VERSION 5.7 ;
  NOWIREEXTENSIONATPIN ON ;
  DIVIDERCHAR "/" ;
  BUSBITCHARS "[]" ;
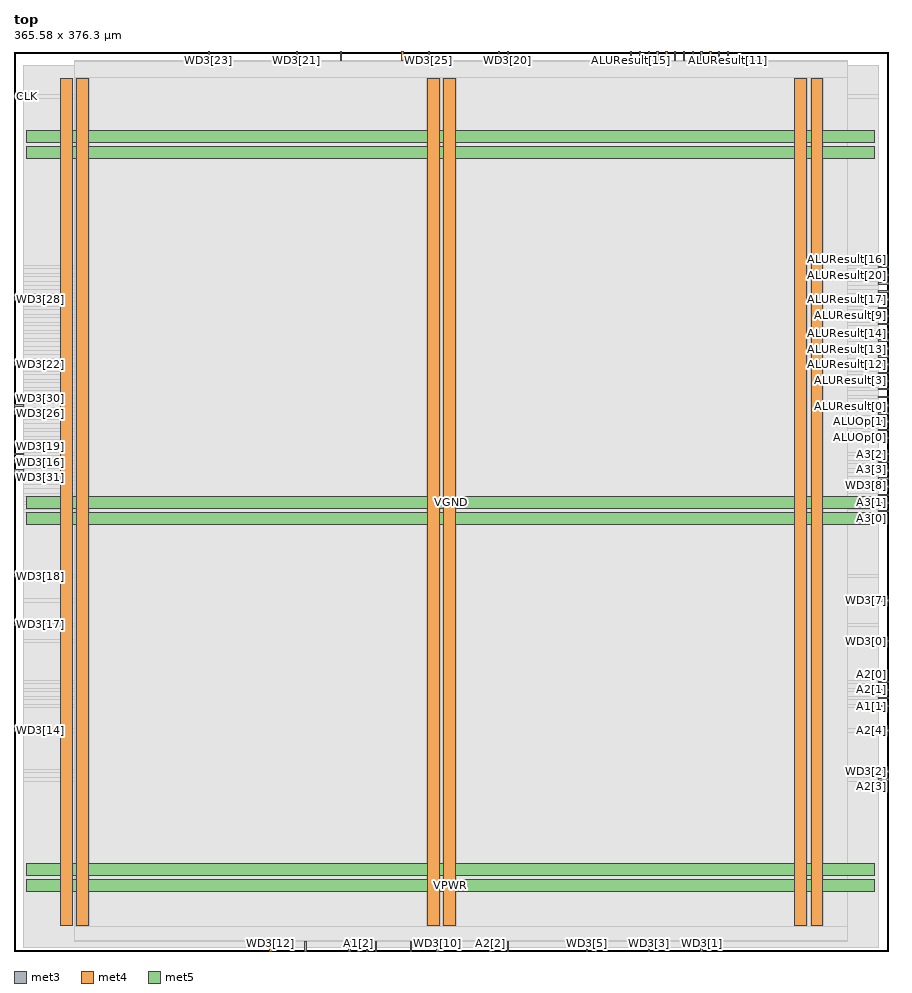
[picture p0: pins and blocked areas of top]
MACRO top
  CLASS BLOCK ;
  FOREIGN top ;
  ORIGIN 0.000 0.000 ;
  SIZE 365.580 BY 376.300 ;
  PIN A1[0]
    DIRECTION INPUT ;
    USE SIGNAL ;
    ANTENNAGATEAREA 0.126000 ;
    PORT
      LAYER met3 ;
        RECT 361.580 105.440 365.580 106.040 ;
    END
  END A1[0]
  PIN A1[1]
    DIRECTION INPUT ;
    USE SIGNAL ;
    ANTENNAGATEAREA 0.196500 ;
    PORT
      LAYER met3 ;
        RECT 361.580 102.040 365.580 102.640 ;
    END
  END A1[1]
  PIN A1[2]
    DIRECTION INPUT ;
    USE SIGNAL ;
    ANTENNAGATEAREA 0.247500 ;
    PORT
      LAYER met4 ;
        RECT 143.680 0.000 144.280 4.000 ;
    END
  END A1[2]
  PIN A1[3]
    DIRECTION INPUT ;
    USE SIGNAL ;
    ANTENNAGATEAREA 0.247500 ;
    PORT
      LAYER met4 ;
        RECT 140.000 0.000 140.600 4.000 ;
    END
  END A1[3]
  PIN A1[4]
    DIRECTION INPUT ;
    USE SIGNAL ;
    ANTENNAGATEAREA 0.213000 ;
    PORT
      LAYER met4 ;
        RECT 147.360 0.000 147.960 4.000 ;
    END
  END A1[4]
  PIN A2[0]
    DIRECTION INPUT ;
    USE SIGNAL ;
    ANTENNAGATEAREA 6.873000 ;
    PORT
      LAYER met3 ;
        RECT 361.580 112.240 365.580 112.840 ;
    END
  END A2[0]
  PIN A2[1]
    DIRECTION INPUT ;
    USE SIGNAL ;
    ANTENNAGATEAREA 0.921000 ;
    PORT
      LAYER met3 ;
        RECT 361.580 108.840 365.580 109.440 ;
    END
  END A2[1]
  PIN A2[2]
    DIRECTION INPUT ;
    USE SIGNAL ;
    ANTENNAGATEAREA 0.196500 ;
    PORT
      LAYER met4 ;
        RECT 198.880 0.000 199.480 4.000 ;
    END
  END A2[2]
  PIN A2[3]
    DIRECTION INPUT ;
    USE SIGNAL ;
    ANTENNAGATEAREA 0.126000 ;
    PORT
      LAYER met3 ;
        RECT 361.580 71.440 365.580 72.040 ;
    END
  END A2[3]
  PIN A2[4]
    DIRECTION INPUT ;
    USE SIGNAL ;
    ANTENNAGATEAREA 0.247500 ;
    PORT
      LAYER met3 ;
        RECT 361.580 91.840 365.580 92.440 ;
    END
  END A2[4]
  PIN A3[0]
    DIRECTION INPUT ;
    USE SIGNAL ;
    ANTENNAGATEAREA 0.213000 ;
    PORT
      LAYER met3 ;
        RECT 361.580 183.640 365.580 184.240 ;
    END
  END A3[0]
  PIN A3[1]
    DIRECTION INPUT ;
    USE SIGNAL ;
    ANTENNAGATEAREA 0.159000 ;
    PORT
      LAYER met3 ;
        RECT 361.580 187.040 365.580 187.640 ;
    END
  END A3[1]
  PIN A3[2]
    DIRECTION INPUT ;
    USE SIGNAL ;
    ANTENNAGATEAREA 0.159000 ;
    PORT
      LAYER met3 ;
        RECT 361.580 207.440 365.580 208.040 ;
    END
  END A3[2]
  PIN A3[3]
    DIRECTION INPUT ;
    USE SIGNAL ;
    ANTENNAGATEAREA 0.159000 ;
    PORT
      LAYER met3 ;
        RECT 361.580 204.040 365.580 204.640 ;
    END
  END A3[3]
  PIN A3[4]
    DIRECTION INPUT ;
    USE SIGNAL ;
    ANTENNAGATEAREA 0.159000 ;
    PORT
      LAYER met3 ;
        RECT 361.580 200.640 365.580 201.240 ;
    END
  END A3[4]
  PIN ALUOp[0]
    DIRECTION INPUT ;
    USE SIGNAL ;
    ANTENNAGATEAREA 0.213000 ;
    PORT
      LAYER met3 ;
        RECT 361.580 214.240 365.580 214.840 ;
    END
  END ALUOp[0]
  PIN ALUOp[1]
    DIRECTION INPUT ;
    USE SIGNAL ;
    ANTENNAGATEAREA 0.213000 ;
    PORT
      LAYER met3 ;
        RECT 361.580 221.040 365.580 221.640 ;
    END
  END ALUOp[1]
  PIN ALUResult[0]
    DIRECTION OUTPUT ;
    USE SIGNAL ;
    ANTENNADIFFAREA 1.336500 ;
    PORT
      LAYER met3 ;
        RECT 361.580 224.440 365.580 225.040 ;
    END
  END ALUResult[0]
  PIN ALUResult[10]
    DIRECTION OUTPUT ;
    USE SIGNAL ;
    ANTENNADIFFAREA 0.445500 ;
    PORT
      LAYER met3 ;
        RECT 361.580 258.440 365.580 259.040 ;
    END
  END ALUResult[10]
  PIN ALUResult[11]
    DIRECTION OUTPUT ;
    USE SIGNAL ;
    ANTENNADIFFAREA 0.795200 ;
    PORT
      LAYER met4 ;
        RECT 298.240 372.300 298.840 376.300 ;
    END
  END ALUResult[11]
  PIN ALUResult[12]
    DIRECTION OUTPUT ;
    USE SIGNAL ;
    ANTENNADIFFAREA 1.336500 ;
    PORT
      LAYER met3 ;
        RECT 361.580 244.840 365.580 245.440 ;
    END
  END ALUResult[12]
  PIN ALUResult[13]
    DIRECTION OUTPUT ;
    USE SIGNAL ;
    ANTENNADIFFAREA 0.445500 ;
    PORT
      LAYER met3 ;
        RECT 361.580 248.240 365.580 248.840 ;
    END
  END ALUResult[13]
  PIN ALUResult[14]
    DIRECTION OUTPUT ;
    USE SIGNAL ;
    ANTENNADIFFAREA 1.336500 ;
    PORT
      LAYER met3 ;
        RECT 361.580 255.040 365.580 255.640 ;
    END
  END ALUResult[14]
  PIN ALUResult[15]
    DIRECTION OUTPUT ;
    USE SIGNAL ;
    ANTENNADIFFAREA 0.795200 ;
    PORT
      LAYER met4 ;
        RECT 257.760 372.300 258.360 376.300 ;
    END
  END ALUResult[15]
  PIN ALUResult[16]
    DIRECTION OUTPUT ;
    USE SIGNAL ;
    ANTENNADIFFAREA 1.336500 ;
    PORT
      LAYER met3 ;
        RECT 361.580 285.640 365.580 286.240 ;
    END
  END ALUResult[16]
  PIN ALUResult[17]
    DIRECTION OUTPUT ;
    USE SIGNAL ;
    ANTENNADIFFAREA 0.445500 ;
    PORT
      LAYER met3 ;
        RECT 361.580 272.040 365.580 272.640 ;
    END
  END ALUResult[17]
  PIN ALUResult[18]
    DIRECTION OUTPUT ;
    USE SIGNAL ;
    ANTENNADIFFAREA 0.795200 ;
    PORT
      LAYER met3 ;
        RECT 361.580 261.840 365.580 262.440 ;
    END
  END ALUResult[18]
  PIN ALUResult[19]
    DIRECTION OUTPUT ;
    USE SIGNAL ;
    ANTENNADIFFAREA 0.445500 ;
    PORT
      LAYER met3 ;
        RECT 361.580 275.440 365.580 276.040 ;
    END
  END ALUResult[19]
  PIN ALUResult[1]
    DIRECTION OUTPUT ;
    USE SIGNAL ;
    ANTENNADIFFAREA 1.336500 ;
    PORT
      LAYER met3 ;
        RECT 361.580 217.640 365.580 218.240 ;
    END
  END ALUResult[1]
  PIN ALUResult[20]
    DIRECTION OUTPUT ;
    USE SIGNAL ;
    ANTENNADIFFAREA 0.445500 ;
    PORT
      LAYER met3 ;
        RECT 361.580 282.240 365.580 282.840 ;
    END
  END ALUResult[20]
  PIN ALUResult[21]
    DIRECTION OUTPUT ;
    USE SIGNAL ;
    ANTENNADIFFAREA 0.445500 ;
    PORT
      LAYER met3 ;
        RECT 361.580 278.840 365.580 279.440 ;
    END
  END ALUResult[21]
  PIN ALUResult[22]
    DIRECTION OUTPUT ;
    USE SIGNAL ;
    ANTENNADIFFAREA 0.795200 ;
    PORT
      LAYER met4 ;
        RECT 265.120 372.300 265.720 376.300 ;
    END
  END ALUResult[22]
  PIN ALUResult[23]
    DIRECTION OUTPUT ;
    USE SIGNAL ;
    ANTENNADIFFAREA 0.795200 ;
    PORT
      LAYER met4 ;
        RECT 261.440 372.300 262.040 376.300 ;
    END
  END ALUResult[23]
  PIN ALUResult[24]
    DIRECTION OUTPUT ;
    USE SIGNAL ;
    ANTENNADIFFAREA 0.795200 ;
    PORT
      LAYER met4 ;
        RECT 268.800 372.300 269.400 376.300 ;
    END
  END ALUResult[24]
  PIN ALUResult[25]
    DIRECTION OUTPUT ;
    USE SIGNAL ;
    ANTENNADIFFAREA 0.795200 ;
    PORT
      LAYER met4 ;
        RECT 294.560 372.300 295.160 376.300 ;
    END
  END ALUResult[25]
  PIN ALUResult[26]
    DIRECTION OUTPUT ;
    USE SIGNAL ;
    ANTENNADIFFAREA 0.795200 ;
    PORT
      LAYER met4 ;
        RECT 272.480 372.300 273.080 376.300 ;
    END
  END ALUResult[26]
  PIN ALUResult[27]
    DIRECTION OUTPUT ;
    USE SIGNAL ;
    ANTENNADIFFAREA 0.795200 ;
    PORT
      LAYER met4 ;
        RECT 279.840 372.300 280.440 376.300 ;
    END
  END ALUResult[27]
  PIN ALUResult[28]
    DIRECTION OUTPUT ;
    USE SIGNAL ;
    ANTENNADIFFAREA 0.795200 ;
    PORT
      LAYER met4 ;
        RECT 290.880 372.300 291.480 376.300 ;
    END
  END ALUResult[28]
  PIN ALUResult[29]
    DIRECTION OUTPUT ;
    USE SIGNAL ;
    ANTENNADIFFAREA 1.782000 ;
    PORT
      LAYER met4 ;
        RECT 276.160 372.300 276.760 376.300 ;
    END
  END ALUResult[29]
  PIN ALUResult[2]
    DIRECTION OUTPUT ;
    USE SIGNAL ;
    ANTENNADIFFAREA 0.445500 ;
    PORT
      LAYER met3 ;
        RECT 361.580 234.640 365.580 235.240 ;
    END
  END ALUResult[2]
  PIN ALUResult[30]
    DIRECTION OUTPUT ;
    USE SIGNAL ;
    ANTENNADIFFAREA 1.336500 ;
    PORT
      LAYER met4 ;
        RECT 283.520 372.300 284.120 376.300 ;
    END
  END ALUResult[30]
  PIN ALUResult[31]
    DIRECTION OUTPUT ;
    USE SIGNAL ;
    ANTENNADIFFAREA 0.795200 ;
    PORT
      LAYER met4 ;
        RECT 287.200 372.300 287.800 376.300 ;
    END
  END ALUResult[31]
  PIN ALUResult[3]
    DIRECTION OUTPUT ;
    USE SIGNAL ;
    ANTENNADIFFAREA 0.445500 ;
    PORT
      LAYER met3 ;
        RECT 361.580 241.440 365.580 242.040 ;
    END
  END ALUResult[3]
  PIN ALUResult[4]
    DIRECTION OUTPUT ;
    USE SIGNAL ;
    ANTENNADIFFAREA 0.445500 ;
    PORT
      LAYER met3 ;
        RECT 361.580 238.040 365.580 238.640 ;
    END
  END ALUResult[4]
  PIN ALUResult[5]
    DIRECTION OUTPUT ;
    USE SIGNAL ;
    ANTENNADIFFAREA 0.445500 ;
    PORT
      LAYER met3 ;
        RECT 361.580 251.640 365.580 252.240 ;
    END
  END ALUResult[5]
  PIN ALUResult[6]
    DIRECTION OUTPUT ;
    USE SIGNAL ;
    ANTENNADIFFAREA 0.445500 ;
    PORT
      LAYER met3 ;
        RECT 361.580 227.840 365.580 228.440 ;
    END
  END ALUResult[6]
  PIN ALUResult[7]
    DIRECTION OUTPUT ;
    USE SIGNAL ;
    ANTENNADIFFAREA 0.445500 ;
    PORT
      LAYER met3 ;
        RECT 361.580 231.240 365.580 231.840 ;
    END
  END ALUResult[7]
  PIN ALUResult[8]
    DIRECTION OUTPUT ;
    USE SIGNAL ;
    ANTENNADIFFAREA 0.445500 ;
    PORT
      LAYER met3 ;
        RECT 361.580 268.640 365.580 269.240 ;
    END
  END ALUResult[8]
  PIN ALUResult[9]
    DIRECTION OUTPUT ;
    USE SIGNAL ;
    ANTENNADIFFAREA 0.445500 ;
    PORT
      LAYER met3 ;
        RECT 361.580 265.240 365.580 265.840 ;
    END
  END ALUResult[9]
  PIN CLK
    DIRECTION INPUT ;
    USE SIGNAL ;
    ANTENNAGATEAREA 0.852000 ;
    PORT
      LAYER met3 ;
        RECT 0.000 357.040 4.000 357.640 ;
    END
  END CLK
  PIN VGND
    DIRECTION INOUT ;
    USE GROUND ;
    PORT
      LAYER met4 ;
        RECT 26.040 10.640 31.040 364.720 ;
    END
    PORT
      LAYER met4 ;
        RECT 179.640 10.640 184.640 364.720 ;
    END
    PORT
      LAYER met4 ;
        RECT 333.240 10.640 338.240 364.720 ;
    END
    PORT
      LAYER met5 ;
        RECT 5.280 31.730 359.960 36.730 ;
    END
    PORT
      LAYER met5 ;
        RECT 5.280 184.910 359.960 189.910 ;
    END
    PORT
      LAYER met5 ;
        RECT 5.280 338.090 359.960 343.090 ;
    END
  END VGND
  PIN VPWR
    DIRECTION INOUT ;
    USE POWER ;
    PORT
      LAYER met4 ;
        RECT 19.340 10.640 24.340 364.720 ;
    END
    PORT
      LAYER met4 ;
        RECT 172.940 10.640 177.940 364.720 ;
    END
    PORT
      LAYER met4 ;
        RECT 326.540 10.640 331.540 364.720 ;
    END
    PORT
      LAYER met5 ;
        RECT 5.280 25.030 359.960 30.030 ;
    END
    PORT
      LAYER met5 ;
        RECT 5.280 178.210 359.960 183.210 ;
    END
    PORT
      LAYER met5 ;
        RECT 5.280 331.390 359.960 336.390 ;
    END
  END VPWR
  PIN WD3[0]
    DIRECTION INPUT ;
    USE SIGNAL ;
    ANTENNAGATEAREA 0.126000 ;
    PORT
      LAYER met3 ;
        RECT 361.580 129.240 365.580 129.840 ;
    END
  END WD3[0]
  PIN WD3[10]
    DIRECTION INPUT ;
    USE SIGNAL ;
    ANTENNAGATEAREA 0.196500 ;
    PORT
      LAYER met4 ;
        RECT 176.800 0.000 177.400 4.000 ;
    END
  END WD3[10]
  PIN WD3[11]
    DIRECTION INPUT ;
    USE SIGNAL ;
    ANTENNAGATEAREA 0.126000 ;
    PORT
      LAYER met4 ;
        RECT 151.040 0.000 151.640 4.000 ;
    END
  END WD3[11]
  PIN WD3[12]
    DIRECTION INPUT ;
    USE SIGNAL ;
    ANTENNAGATEAREA 0.196500 ;
    PORT
      LAYER met4 ;
        RECT 106.880 0.000 107.480 4.000 ;
    END
  END WD3[12]
  PIN WD3[13]
    DIRECTION INPUT ;
    USE SIGNAL ;
    ANTENNAGATEAREA 0.196500 ;
    PORT
      LAYER met4 ;
        RECT 121.600 0.000 122.200 4.000 ;
    END
  END WD3[13]
  PIN WD3[14]
    DIRECTION INPUT ;
    USE SIGNAL ;
    ANTENNAGATEAREA 0.196500 ;
    PORT
      LAYER met3 ;
        RECT 0.000 91.840 4.000 92.440 ;
    END
  END WD3[14]
  PIN WD3[15]
    DIRECTION INPUT ;
    USE SIGNAL ;
    ANTENNAGATEAREA 0.213000 ;
    PORT
      LAYER met4 ;
        RECT 165.760 0.000 166.360 4.000 ;
    END
  END WD3[15]
  PIN WD3[16]
    DIRECTION INPUT ;
    USE SIGNAL ;
    ANTENNAGATEAREA 0.196500 ;
    PORT
      LAYER met3 ;
        RECT 0.000 204.040 4.000 204.640 ;
    END
  END WD3[16]
  PIN WD3[17]
    DIRECTION INPUT ;
    USE SIGNAL ;
    ANTENNAGATEAREA 0.196500 ;
    PORT
      LAYER met3 ;
        RECT 0.000 136.040 4.000 136.640 ;
    END
  END WD3[17]
  PIN WD3[18]
    DIRECTION INPUT ;
    USE SIGNAL ;
    ANTENNAGATEAREA 0.213000 ;
    PORT
      LAYER met3 ;
        RECT 0.000 156.440 4.000 157.040 ;
    END
  END WD3[18]
  PIN WD3[19]
    DIRECTION INPUT ;
    USE SIGNAL ;
    ANTENNAGATEAREA 0.196500 ;
    PORT
      LAYER met3 ;
        RECT 0.000 207.440 4.000 208.040 ;
    END
  END WD3[19]
  PIN WD3[1]
    DIRECTION INPUT ;
    USE SIGNAL ;
    ANTENNAGATEAREA 0.196500 ;
    PORT
      LAYER met4 ;
        RECT 287.200 0.000 287.800 4.000 ;
    END
  END WD3[1]
  PIN WD3[20]
    DIRECTION INPUT ;
    USE SIGNAL ;
    ANTENNAGATEAREA 0.213000 ;
    PORT
      LAYER met4 ;
        RECT 206.240 372.300 206.840 376.300 ;
    END
  END WD3[20]
  PIN WD3[21]
    DIRECTION INPUT ;
    USE SIGNAL ;
    ANTENNAGATEAREA 0.196500 ;
    PORT
      LAYER met4 ;
        RECT 117.920 372.300 118.520 376.300 ;
    END
  END WD3[21]
  PIN WD3[22]
    DIRECTION INPUT ;
    USE SIGNAL ;
    ANTENNAGATEAREA 0.126000 ;
    PORT
      LAYER met3 ;
        RECT 0.000 244.840 4.000 245.440 ;
    END
  END WD3[22]
  PIN WD3[23]
    DIRECTION INPUT ;
    USE SIGNAL ;
    ANTENNAGATEAREA 0.196500 ;
    PORT
      LAYER met4 ;
        RECT 81.120 372.300 81.720 376.300 ;
    END
  END WD3[23]
  PIN WD3[24]
    DIRECTION INPUT ;
    USE SIGNAL ;
    ANTENNAGATEAREA 0.126000 ;
    PORT
      LAYER met4 ;
        RECT 202.560 372.300 203.160 376.300 ;
    END
  END WD3[24]
  PIN WD3[25]
    DIRECTION INPUT ;
    USE SIGNAL ;
    ANTENNAGATEAREA 0.196500 ;
    PORT
      LAYER met4 ;
        RECT 173.120 372.300 173.720 376.300 ;
    END
  END WD3[25]
  PIN WD3[26]
    DIRECTION INPUT ;
    USE SIGNAL ;
    ANTENNAGATEAREA 0.126000 ;
    PORT
      LAYER met3 ;
        RECT 0.000 224.440 4.000 225.040 ;
    END
  END WD3[26]
  PIN WD3[27]
    DIRECTION INPUT ;
    USE SIGNAL ;
    ANTENNAGATEAREA 0.126000 ;
    PORT
      LAYER met4 ;
        RECT 162.080 372.300 162.680 376.300 ;
    END
  END WD3[27]
  PIN WD3[28]
    DIRECTION INPUT ;
    USE SIGNAL ;
    ANTENNAGATEAREA 0.126000 ;
    PORT
      LAYER met3 ;
        RECT 0.000 272.040 4.000 272.640 ;
    END
  END WD3[28]
  PIN WD3[29]
    DIRECTION INPUT ;
    USE SIGNAL ;
    ANTENNAGATEAREA 0.126000 ;
    PORT
      LAYER met4 ;
        RECT 136.320 372.300 136.920 376.300 ;
    END
  END WD3[29]
  PIN WD3[2]
    DIRECTION INPUT ;
    USE SIGNAL ;
    ANTENNAGATEAREA 0.196500 ;
    PORT
      LAYER met3 ;
        RECT 361.580 74.840 365.580 75.440 ;
    END
  END WD3[2]
  PIN WD3[30]
    DIRECTION INPUT ;
    USE SIGNAL ;
    ANTENNAGATEAREA 0.213000 ;
    PORT
      LAYER met3 ;
        RECT 0.000 227.840 4.000 228.440 ;
    END
  END WD3[30]
  PIN WD3[31]
    DIRECTION INPUT ;
    USE SIGNAL ;
    ANTENNAGATEAREA 0.213000 ;
    PORT
      LAYER met3 ;
        RECT 0.000 200.640 4.000 201.240 ;
    END
  END WD3[31]
  PIN WD3[3]
    DIRECTION INPUT ;
    USE SIGNAL ;
    ANTENNAGATEAREA 0.126000 ;
    PORT
      LAYER met4 ;
        RECT 265.120 0.000 265.720 4.000 ;
    END
  END WD3[3]
  PIN WD3[4]
    DIRECTION INPUT ;
    USE SIGNAL ;
    ANTENNAGATEAREA 0.196500 ;
    PORT
      LAYER met4 ;
        RECT 206.240 0.000 206.840 4.000 ;
    END
  END WD3[4]
  PIN WD3[5]
    DIRECTION INPUT ;
    USE SIGNAL ;
    ANTENNAGATEAREA 0.196500 ;
    PORT
      LAYER met4 ;
        RECT 239.360 0.000 239.960 4.000 ;
    END
  END WD3[5]
  PIN WD3[6]
    DIRECTION INPUT ;
    USE SIGNAL ;
    ANTENNAGATEAREA 0.213000 ;
    PORT
      LAYER met4 ;
        RECT 243.040 0.000 243.640 4.000 ;
    END
  END WD3[6]
  PIN WD3[7]
    DIRECTION INPUT ;
    USE SIGNAL ;
    ANTENNAGATEAREA 0.213000 ;
    PORT
      LAYER met3 ;
        RECT 361.580 146.240 365.580 146.840 ;
    END
  END WD3[7]
  PIN WD3[8]
    DIRECTION INPUT ;
    USE SIGNAL ;
    ANTENNAGATEAREA 0.196500 ;
    PORT
      LAYER met3 ;
        RECT 361.580 197.240 365.580 197.840 ;
    END
  END WD3[8]
  PIN WD3[9]
    DIRECTION INPUT ;
    USE SIGNAL ;
    ANTENNAGATEAREA 0.213000 ;
    PORT
      LAYER met3 ;
        RECT 361.580 193.840 365.580 194.440 ;
    END
  END WD3[9]
  PIN WE3
    DIRECTION INPUT ;
    USE SIGNAL ;
    ANTENNAGATEAREA 0.213000 ;
    PORT
      LAYER met3 ;
        RECT 361.580 190.440 365.580 191.040 ;
    END
  END WE3
  OBS
      LAYER nwell ;
        RECT 5.330 10.795 359.910 364.565 ;
      LAYER li1 ;
        RECT 5.520 10.795 359.720 364.565 ;
      LAYER met1 ;
        RECT 4.210 10.640 359.720 364.720 ;
      LAYER met2 ;
        RECT 4.230 1.515 358.250 370.445 ;
      LAYER met3 ;
        RECT 3.990 358.040 361.580 370.425 ;
        RECT 4.400 356.640 361.580 358.040 ;
        RECT 3.990 286.640 361.580 356.640 ;
        RECT 3.990 285.240 361.180 286.640 ;
        RECT 3.990 283.240 361.580 285.240 ;
        RECT 3.990 281.840 361.180 283.240 ;
        RECT 3.990 279.840 361.580 281.840 ;
        RECT 3.990 278.440 361.180 279.840 ;
        RECT 3.990 276.440 361.580 278.440 ;
        RECT 3.990 275.040 361.180 276.440 ;
        RECT 3.990 273.040 361.580 275.040 ;
        RECT 4.400 271.640 361.180 273.040 ;
        RECT 3.990 269.640 361.580 271.640 ;
        RECT 3.990 268.240 361.180 269.640 ;
        RECT 3.990 266.240 361.580 268.240 ;
        RECT 3.990 264.840 361.180 266.240 ;
        RECT 3.990 262.840 361.580 264.840 ;
        RECT 3.990 261.440 361.180 262.840 ;
        RECT 3.990 259.440 361.580 261.440 ;
        RECT 3.990 258.040 361.180 259.440 ;
        RECT 3.990 256.040 361.580 258.040 ;
        RECT 3.990 254.640 361.180 256.040 ;
        RECT 3.990 252.640 361.580 254.640 ;
        RECT 3.990 251.240 361.180 252.640 ;
        RECT 3.990 249.240 361.580 251.240 ;
        RECT 3.990 247.840 361.180 249.240 ;
        RECT 3.990 245.840 361.580 247.840 ;
        RECT 4.400 244.440 361.180 245.840 ;
        RECT 3.990 242.440 361.580 244.440 ;
        RECT 3.990 241.040 361.180 242.440 ;
        RECT 3.990 239.040 361.580 241.040 ;
        RECT 3.990 237.640 361.180 239.040 ;
        RECT 3.990 235.640 361.580 237.640 ;
        RECT 3.990 234.240 361.180 235.640 ;
        RECT 3.990 232.240 361.580 234.240 ;
        RECT 3.990 230.840 361.180 232.240 ;
        RECT 3.990 228.840 361.580 230.840 ;
        RECT 4.400 227.440 361.180 228.840 ;
        RECT 3.990 225.440 361.580 227.440 ;
        RECT 4.400 224.040 361.180 225.440 ;
        RECT 3.990 222.040 361.580 224.040 ;
        RECT 3.990 220.640 361.180 222.040 ;
        RECT 3.990 218.640 361.580 220.640 ;
        RECT 3.990 217.240 361.180 218.640 ;
        RECT 3.990 215.240 361.580 217.240 ;
        RECT 3.990 213.840 361.180 215.240 ;
        RECT 3.990 208.440 361.580 213.840 ;
        RECT 4.400 207.040 361.180 208.440 ;
        RECT 3.990 205.040 361.580 207.040 ;
        RECT 4.400 203.640 361.180 205.040 ;
        RECT 3.990 201.640 361.580 203.640 ;
        RECT 4.400 200.240 361.180 201.640 ;
        RECT 3.990 198.240 361.580 200.240 ;
        RECT 3.990 196.840 361.180 198.240 ;
        RECT 3.990 194.840 361.580 196.840 ;
        RECT 3.990 193.440 361.180 194.840 ;
        RECT 3.990 191.440 361.580 193.440 ;
        RECT 3.990 190.040 361.180 191.440 ;
        RECT 3.990 188.040 361.580 190.040 ;
        RECT 3.990 186.640 361.180 188.040 ;
        RECT 3.990 184.640 361.580 186.640 ;
        RECT 3.990 183.240 361.180 184.640 ;
        RECT 3.990 157.440 361.580 183.240 ;
        RECT 4.400 156.040 361.580 157.440 ;
        RECT 3.990 147.240 361.580 156.040 ;
        RECT 3.990 145.840 361.180 147.240 ;
        RECT 3.990 137.040 361.580 145.840 ;
        RECT 4.400 135.640 361.580 137.040 ;
        RECT 3.990 130.240 361.580 135.640 ;
        RECT 3.990 128.840 361.180 130.240 ;
        RECT 3.990 113.240 361.580 128.840 ;
        RECT 3.990 111.840 361.180 113.240 ;
        RECT 3.990 109.840 361.580 111.840 ;
        RECT 3.990 108.440 361.180 109.840 ;
        RECT 3.990 106.440 361.580 108.440 ;
        RECT 3.990 105.040 361.180 106.440 ;
        RECT 3.990 103.040 361.580 105.040 ;
        RECT 3.990 101.640 361.180 103.040 ;
        RECT 3.990 92.840 361.580 101.640 ;
        RECT 4.400 91.440 361.180 92.840 ;
        RECT 3.990 75.840 361.580 91.440 ;
        RECT 3.990 74.440 361.180 75.840 ;
        RECT 3.990 72.440 361.580 74.440 ;
        RECT 3.990 71.040 361.180 72.440 ;
        RECT 3.990 1.535 361.580 71.040 ;
      LAYER met4 ;
        RECT 25.135 371.900 80.720 372.300 ;
        RECT 82.120 371.900 117.520 372.300 ;
        RECT 118.920 371.900 135.920 372.300 ;
        RECT 137.320 371.900 161.680 372.300 ;
        RECT 163.080 371.900 172.720 372.300 ;
        RECT 174.120 371.900 202.160 372.300 ;
        RECT 203.560 371.900 205.840 372.300 ;
        RECT 207.240 371.900 257.360 372.300 ;
        RECT 258.760 371.900 261.040 372.300 ;
        RECT 262.440 371.900 264.720 372.300 ;
        RECT 266.120 371.900 268.400 372.300 ;
        RECT 269.800 371.900 272.080 372.300 ;
        RECT 273.480 371.900 275.760 372.300 ;
        RECT 277.160 371.900 279.440 372.300 ;
        RECT 280.840 371.900 283.120 372.300 ;
        RECT 284.520 371.900 286.800 372.300 ;
        RECT 288.200 371.900 290.480 372.300 ;
        RECT 291.880 371.900 294.160 372.300 ;
        RECT 295.560 371.900 297.840 372.300 ;
        RECT 299.240 371.900 348.385 372.300 ;
        RECT 25.135 365.120 348.385 371.900 ;
        RECT 25.135 10.240 25.640 365.120 ;
        RECT 31.440 10.240 172.540 365.120 ;
        RECT 178.340 10.240 179.240 365.120 ;
        RECT 185.040 10.240 326.140 365.120 ;
        RECT 331.940 10.240 332.840 365.120 ;
        RECT 338.640 10.240 348.385 365.120 ;
        RECT 25.135 4.400 348.385 10.240 ;
        RECT 25.135 4.000 106.480 4.400 ;
        RECT 107.880 4.000 121.200 4.400 ;
        RECT 122.600 4.000 139.600 4.400 ;
        RECT 141.000 4.000 143.280 4.400 ;
        RECT 144.680 4.000 146.960 4.400 ;
        RECT 148.360 4.000 150.640 4.400 ;
        RECT 152.040 4.000 165.360 4.400 ;
        RECT 166.760 4.000 176.400 4.400 ;
        RECT 177.800 4.000 198.480 4.400 ;
        RECT 199.880 4.000 205.840 4.400 ;
        RECT 207.240 4.000 238.960 4.400 ;
        RECT 240.360 4.000 242.640 4.400 ;
        RECT 244.040 4.000 264.720 4.400 ;
        RECT 266.120 4.000 286.800 4.400 ;
        RECT 288.200 4.000 348.385 4.400 ;
  END
END top
END LIBRARY

